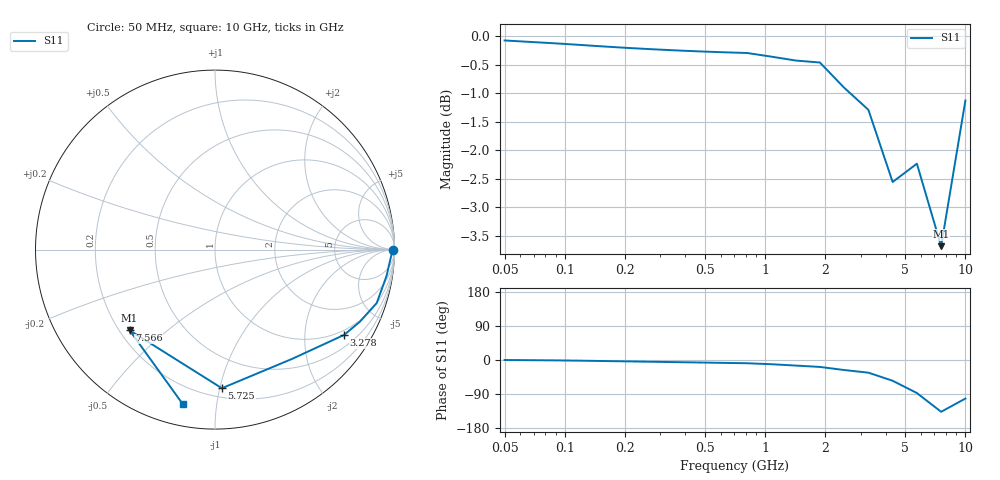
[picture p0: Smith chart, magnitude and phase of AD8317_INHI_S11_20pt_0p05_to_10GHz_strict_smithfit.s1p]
! AD8317 INHI/INLO input model, 0.05-10 GHz
! Sources: AD8317 Rev.D pp.3-4 impedance table + p.9 Figure 15 approximation
! INLO is RF common (AC-coupled to ground), modeled implicitly in single-ended S11 at INHI.
# GHZ S RI R 50
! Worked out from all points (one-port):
!   20 points, 50 MHz to 10 GHz, reference 50 ohm
!   lowest |S11| = -3.7 dB at 7.566 GHz (marker M1), VSWR 4.79, Z = 12 - j18.9 ohm
!   |S11| at or under -10 dB: nowhere
!   S11 on the Smith chart (normalised r, x): 50 MHz: open; 3.278 GHz: 0.84, -3.12; 5.725 GHz: 0.26, -1.02; 7.566 GHz: 0.24, -0.38; 10 GHz: 0.11, -0.81
0.05  0.992 0
0.066081  0.9892 -0.00805
0.087334  0.9864 -0.0161
0.115423  0.983 -0.0285
0.152545  0.9792 -0.045
0.201606  0.9754 -0.0615
0.266447  0.9716 -0.078
0.352142  0.9678 -0.0945
0.465398  0.964 -0.111
0.61508  0.9602 -0.1275
0.812902  0.9564 -0.144
1.074349  0.942 -0.1855
1.419882  0.9214 -0.2415
1.876545  0.9009 -0.2975
2.480081  0.8073 -0.4016
3.277726  0.7195 -0.4752
4.33191  0.43 -0.6087
5.725143  0.0382 -0.7724
7.566467  -0.476 -0.4493
10  -0.18 -0.86
